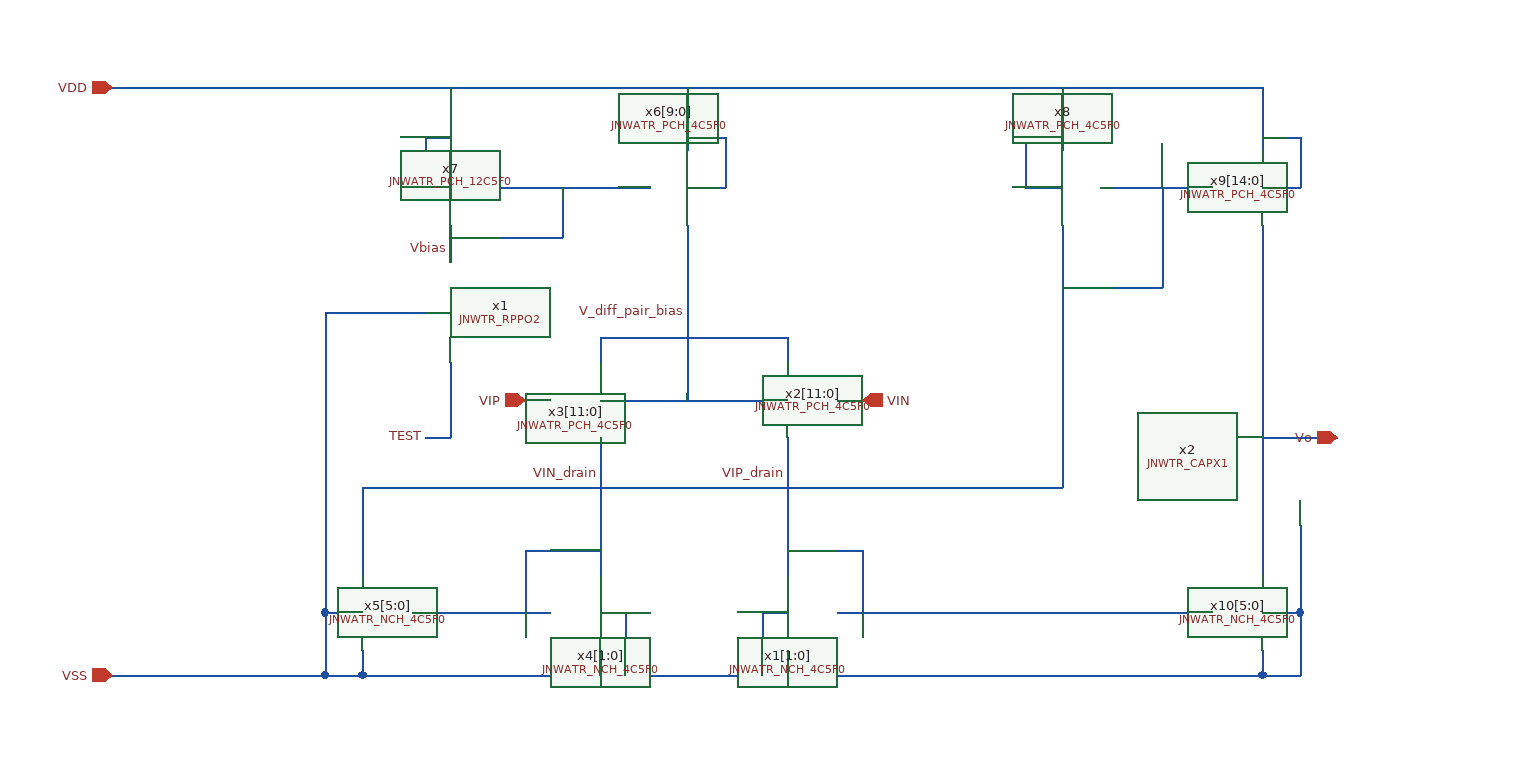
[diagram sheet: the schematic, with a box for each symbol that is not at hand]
v {xschem version=3.4.6 file_version=1.2}
G {}
K {}
V {}
S {}
E {}
N -20 -180 -20 -70 {lab=VIP_drain}
N -170 -180 -170 -70 {lab=VIN_drain}
N -170 -260 -170 -240 {lab=V_diff_pair_bias}
N -20 -260 -20 -240 {lab=V_diff_pair_bias}
N -170 -10 -170 10 {lab=VSS}
N -190 10 -20 10 {lab=VSS}
N -20 -10 -20 10 {lab=VSS}
N -100 -290 -100 -260 {lab=V_diff_pair_bias}
N -300 -40 -210 -40 {lab=VIN_drain}
N -250 -380 -130 -380 {lab=Vbias}
N -290 -350 -290 -320 {lab=Vbias}
N -100 -350 -100 -290 {lab=V_diff_pair_bias}
N 20 -40 130 -40 {lab=VIP_drain}
N -560 -460 360 -460 {lab=VDD}
N -290 -460 -290 -410 {lab=VDD}
N -100 -460 -100 -410 {lab=VDD}
N 200 -460 200 -410 {lab=VDD}
N 130 -40 320 -40 {lab=VIP_drain}
N 360 -460 360 -410 {lab=VDD}
N 360 -350 360 -70 {lab=Vo}
N 230 -380 320 -380 {lab=#net1}
N 280 -380 280 -300 {lab=#net1}
N 200 -300 280 -300 {lab=#net1}
N -360 -100 -360 -70 {lab=#net1}
N -170 -40 -150 -40 {lab=VSS}
N -150 -40 -150 0 {lab=VSS}
N -40 -40 -20 -40 {lab=VSS}
N -40 -40 -40 -0 {lab=VSS}
N -390 -40 -360 -40 {lab=VSS}
N -390 -40 -390 10 {lab=VSS}
N -390 10 -360 10 {lab=VSS}
N 360 -40 390 -40 {lab=VSS}
N 390 -40 390 10 {lab=VSS}
N 360 10 390 10 {lab=VSS}
N -310 -380 -290 -380 {lab=VDD}
N -310 -420 -310 -380 {lab=VDD}
N -310 -420 -290 -420 {lab=VDD}
N -100 -380 -70 -380 {lab=VDD}
N -70 -420 -70 -380 {lab=VDD}
N -100 -420 -70 -420 {lab=VDD}
N 170 -380 200 -380 {lab=VDD}
N 170 -420 170 -380 {lab=VDD}
N 170 -420 200 -420 {lab=VDD}
N 360 -380 390 -380 {lab=VDD}
N 390 -420 390 -380 {lab=VDD}
N 360 -420 390 -420 {lab=VDD}
N -40 -210 -20 -210 {lab=V_diff_pair_bias}
N -170 -210 -140 -210 {lab=V_diff_pair_bias}
N -290 -340 -200 -340 {lab=Vbias}
N -200 -380 -200 -340 {lab=Vbias}
N 360 -180 380 -180 {lab=Vo}
N -410 10 -390 10 {lab=VSS}
N -360 -10 -360 10 {lab=VSS}
N 360 -10 360 10 {lab=VSS}
N -360 -140 -360 -100 {lab=#net1}
N 200 -350 200 -140 {lab=#net1}
N -560 10 -410 10 {lab=VSS}
N -390 -280 -310 -280 {lab=VSS}
N -390 -280 -390 -40 {lab=VSS}
N -290 -240 -290 -190 {lab=TEST}
N -290 -190 -290 -180 {lab=TEST}
N -310 -180 -290 -180 {lab=TEST}
N -220 -210 -210 -210 {lab=VIP}
N -170 -260 -20 -260 {lab=V_diff_pair_bias}
N -230 -90 -170 -90 {lab=VIN_drain}
N -230 -90 -230 -40 {lab=VIN_drain}
N -320 -40 -300 -40 {lab=VIN_drain}
N -230 -210 -220 -210 {lab=VIP}
N 20 -210 40 -210 {lab=VIN}
N -140 -210 -40 -210 {lab=V_diff_pair_bias}
N -360 -140 200 -140 {lab=#net1}
N -360 10 -190 10 {lab=VSS}
N -20 10 360 10 {lab=VSS}
N -150 0 -150 10 {lab=VSS}
N -40 -0 -40 10 {lab=VSS}
N -20 -90 40 -90 {lab=VIP_drain}
N 40 -90 40 -40 {lab=VIP_drain}
N 380 -180 400 -180 {lab=Vo}
N 400 -180 420 -180 {lab=Vo}
N -100 -260 -100 -210 {lab=V_diff_pair_bias}
N 390 -110 390 -40 {}
C {JNW_ATR_SKY130A/JNWATR_NCH_4C5F0.sym} 20 -40 0 1 {name=x1[1:0]}
C {JNW_ATR_SKY130A/JNWATR_NCH_4C5F0.sym} -210 -40 0 0 {name=x4[1:0]}
C {JNW_ATR_SKY130A/JNWATR_PCH_4C5F0.sym} -210 -210 0 0 {name=x3[11:0]}
C {JNW_ATR_SKY130A/JNWATR_PCH_4C5F0.sym} 20 -210 0 1 {name=x2[11:0]}
C {JNW_ATR_SKY130A/JNWATR_NCH_4C5F0.sym} -320 -40 0 1 {name=x5[5:0]}
C {JNW_ATR_SKY130A/JNWATR_PCH_4C5F0.sym} -140 -380 0 0 {name=x6[9:0]}
C {JNW_ATR_SKY130A/JNWATR_PCH_12C5F0.sym} -250 -380 0 1 {name=x7}
C {JNW_ATR_SKY130A/JNWATR_PCH_4C5F0.sym} 240 -380 0 1 {name=x8
}
C {JNW_ATR_SKY130A/JNWATR_PCH_4C5F0.sym} 320 -380 0 0 {name=x9[14:0]
}
C {JNW_ATR_SKY130A/JNWATR_NCH_4C5F0.sym} 320 -40 0 0 {name=x10[5:0]
}
C {devices/ipin.sym} -560 -460 0 0 {name=p1 lab=VDD
}
C {devices/ipin.sym} -230 -210 0 0 {name=p2 lab=VIP

}
C {devices/ipin.sym} 40 -210 0 1 {name=p3 lab=VIN


}
C {devices/ipin.sym} -560 10 0 0 {name=p4 lab=VSS
}
C {devices/iopin.sym} 420 -180 0 0 {name=p5 lab=Vo
}
C {devices/lab_wire.sym} -290 -330 0 0 {name=p7 sig_type=std_logic lab=Vbias
}
C {JNW_TR_SKY130A/JNWTR_RPPO2.sym} -290 -240 1 1 {name=x1}
C {devices/lab_pin.sym} -310 -180 0 0 {name=p6 sig_type=std_logic lab=TEST}
C {devices/lab_wire.sym} -20 -150 0 0 {name=p8 sig_type=std_logic lab=VIP_drain}
C {devices/lab_wire.sym} -170 -150 0 0 {name=p9 sig_type=std_logic lab=VIN_drain}
C {devices/lab_wire.sym} -100 -280 0 0 {name=p10 sig_type=std_logic lab=V_diff_pair_bias}
C {JNW_TR_SKY130A/JNWTR_CAPX1.sym} 390 -120 0 0 {name=x2 }
